VERSION 5.7 ;
  NOWIREEXTENSIONATPIN ON ;
  DIVIDERCHAR "/" ;
  BUSBITCHARS "[]" ;
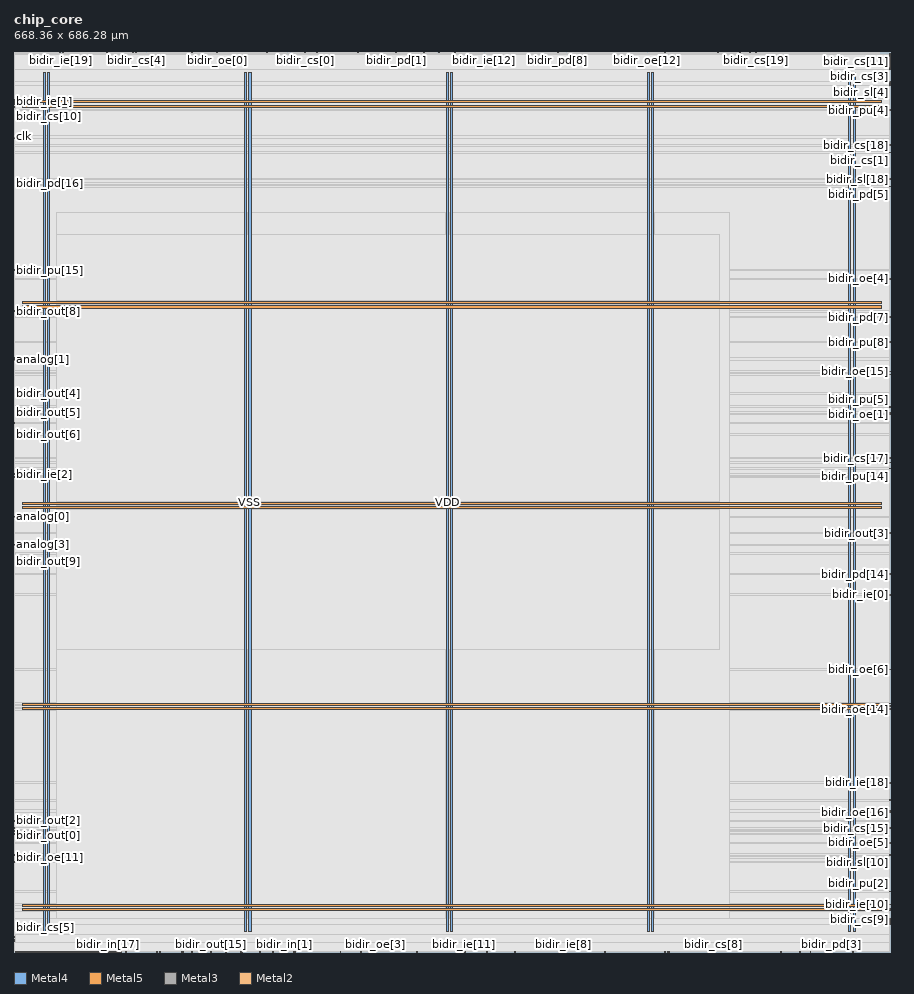
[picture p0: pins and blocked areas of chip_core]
MACRO chip_core
  CLASS BLOCK ;
  FOREIGN chip_core ;
  ORIGIN 0.000 0.000 ;
  SIZE 668.360 BY 686.280 ;
  PIN VDD
    DIRECTION INOUT ;
    USE POWER ;
    PORT
      LAYER Metal4 ;
        RECT 22.240 15.380 23.840 670.620 ;
    END
    PORT
      LAYER Metal4 ;
        RECT 175.840 15.380 177.440 670.620 ;
    END
    PORT
      LAYER Metal4 ;
        RECT 329.440 15.380 331.040 670.620 ;
    END
    PORT
      LAYER Metal4 ;
        RECT 483.040 15.380 484.640 670.620 ;
    END
    PORT
      LAYER Metal4 ;
        RECT 636.640 15.380 638.240 670.620 ;
    END
    PORT
      LAYER Metal5 ;
        RECT 6.720 31.530 661.360 33.130 ;
    END
    PORT
      LAYER Metal5 ;
        RECT 6.720 184.710 661.360 186.310 ;
    END
    PORT
      LAYER Metal5 ;
        RECT 6.720 337.890 661.360 339.490 ;
    END
    PORT
      LAYER Metal5 ;
        RECT 6.720 491.070 661.360 492.670 ;
    END
    PORT
      LAYER Metal5 ;
        RECT 6.720 644.250 661.360 645.850 ;
    END
  END VDD
  PIN VSS
    DIRECTION INOUT ;
    USE GROUND ;
    PORT
      LAYER Metal4 ;
        RECT 25.540 15.380 27.140 670.620 ;
    END
    PORT
      LAYER Metal4 ;
        RECT 179.140 15.380 180.740 670.620 ;
    END
    PORT
      LAYER Metal4 ;
        RECT 332.740 15.380 334.340 670.620 ;
    END
    PORT
      LAYER Metal4 ;
        RECT 486.340 15.380 487.940 670.620 ;
    END
    PORT
      LAYER Metal4 ;
        RECT 639.940 15.380 641.540 670.620 ;
    END
    PORT
      LAYER Metal5 ;
        RECT 6.720 34.830 661.360 36.430 ;
    END
    PORT
      LAYER Metal5 ;
        RECT 6.720 188.010 661.360 189.610 ;
    END
    PORT
      LAYER Metal5 ;
        RECT 6.720 341.190 661.360 342.790 ;
    END
    PORT
      LAYER Metal5 ;
        RECT 6.720 494.370 661.360 495.970 ;
    END
    PORT
      LAYER Metal5 ;
        RECT 6.720 647.550 661.360 649.150 ;
    END
  END VSS
  PIN analog[0]
    DIRECTION INOUT ;
    USE SIGNAL ;
    ANTENNAGATEAREA 1.017500 ;
    PORT
      LAYER Metal3 ;
        RECT 0.000 331.520 0.560 332.080 ;
    END
  END analog[0]
  PIN analog[10]
    DIRECTION INOUT ;
    USE SIGNAL ;
    PORT
      LAYER Metal2 ;
        RECT 1.120 0.000 1.680 0.560 ;
    END
  END analog[10]
  PIN analog[11]
    DIRECTION INOUT ;
    USE SIGNAL ;
    PORT
      LAYER Metal2 ;
        RECT 2.240 0.000 2.800 0.560 ;
    END
  END analog[11]
  PIN analog[12]
    DIRECTION INOUT ;
    USE SIGNAL ;
    PORT
      LAYER Metal2 ;
        RECT 3.360 0.000 3.920 0.560 ;
    END
  END analog[12]
  PIN analog[13]
    DIRECTION INOUT ;
    USE SIGNAL ;
    PORT
      LAYER Metal2 ;
        RECT 4.480 0.000 5.040 0.560 ;
    END
  END analog[13]
  PIN analog[14]
    DIRECTION INOUT ;
    USE SIGNAL ;
    PORT
      LAYER Metal2 ;
        RECT 5.600 0.000 6.160 0.560 ;
    END
  END analog[14]
  PIN analog[15]
    DIRECTION INOUT ;
    USE SIGNAL ;
    PORT
      LAYER Metal2 ;
        RECT 6.720 0.000 7.280 0.560 ;
    END
  END analog[15]
  PIN analog[16]
    DIRECTION INOUT ;
    USE SIGNAL ;
    PORT
      LAYER Metal2 ;
        RECT 7.840 0.000 8.400 0.560 ;
    END
  END analog[16]
  PIN analog[17]
    DIRECTION INOUT ;
    USE SIGNAL ;
    PORT
      LAYER Metal2 ;
        RECT 8.960 0.000 9.520 0.560 ;
    END
  END analog[17]
  PIN analog[18]
    DIRECTION INOUT ;
    USE SIGNAL ;
    PORT
      LAYER Metal2 ;
        RECT 10.080 0.000 10.640 0.560 ;
    END
  END analog[18]
  PIN analog[19]
    DIRECTION INOUT ;
    USE SIGNAL ;
    PORT
      LAYER Metal2 ;
        RECT 11.200 0.000 11.760 0.560 ;
    END
  END analog[19]
  PIN analog[1]
    DIRECTION INOUT ;
    USE SIGNAL ;
    ANTENNAGATEAREA 1.536500 ;
    ANTENNADIFFAREA 0.893200 ;
    PORT
      LAYER Metal3 ;
        RECT 0.000 451.360 0.560 451.920 ;
    END
  END analog[1]
  PIN analog[20]
    DIRECTION INOUT ;
    USE SIGNAL ;
    PORT
      LAYER Metal2 ;
        RECT 12.320 0.000 12.880 0.560 ;
    END
  END analog[20]
  PIN analog[21]
    DIRECTION INOUT ;
    USE SIGNAL ;
    PORT
      LAYER Metal2 ;
        RECT 13.440 0.000 14.000 0.560 ;
    END
  END analog[21]
  PIN analog[22]
    DIRECTION INOUT ;
    USE SIGNAL ;
    PORT
      LAYER Metal2 ;
        RECT 14.560 0.000 15.120 0.560 ;
    END
  END analog[22]
  PIN analog[23]
    DIRECTION INOUT ;
    USE SIGNAL ;
    PORT
      LAYER Metal2 ;
        RECT 15.680 0.000 16.240 0.560 ;
    END
  END analog[23]
  PIN analog[24]
    DIRECTION INOUT ;
    USE SIGNAL ;
    PORT
      LAYER Metal2 ;
        RECT 16.800 0.000 17.360 0.560 ;
    END
  END analog[24]
  PIN analog[25]
    DIRECTION INOUT ;
    USE SIGNAL ;
    PORT
      LAYER Metal2 ;
        RECT 17.920 0.000 18.480 0.560 ;
    END
  END analog[25]
  PIN analog[26]
    DIRECTION INOUT ;
    USE SIGNAL ;
    PORT
      LAYER Metal2 ;
        RECT 19.040 0.000 19.600 0.560 ;
    END
  END analog[26]
  PIN analog[27]
    DIRECTION INOUT ;
    USE SIGNAL ;
    PORT
      LAYER Metal2 ;
        RECT 20.160 0.000 20.720 0.560 ;
    END
  END analog[27]
  PIN analog[28]
    DIRECTION INOUT ;
    USE SIGNAL ;
    PORT
      LAYER Metal2 ;
        RECT 21.280 0.000 21.840 0.560 ;
    END
  END analog[28]
  PIN analog[29]
    DIRECTION INOUT ;
    USE SIGNAL ;
    PORT
      LAYER Metal2 ;
        RECT 22.400 0.000 22.960 0.560 ;
    END
  END analog[29]
  PIN analog[2]
    DIRECTION INOUT ;
    USE SIGNAL ;
    ANTENNAGATEAREA 0.894500 ;
    ANTENNADIFFAREA 0.893200 ;
    PORT
      LAYER Metal3 ;
        RECT 0.000 452.480 0.560 453.040 ;
    END
  END analog[2]
  PIN analog[30]
    DIRECTION INOUT ;
    USE SIGNAL ;
    PORT
      LAYER Metal2 ;
        RECT 23.520 0.000 24.080 0.560 ;
    END
  END analog[30]
  PIN analog[31]
    DIRECTION INOUT ;
    USE SIGNAL ;
    PORT
      LAYER Metal2 ;
        RECT 24.640 0.000 25.200 0.560 ;
    END
  END analog[31]
  PIN analog[32]
    DIRECTION INOUT ;
    USE SIGNAL ;
    PORT
      LAYER Metal2 ;
        RECT 25.760 0.000 26.320 0.560 ;
    END
  END analog[32]
  PIN analog[33]
    DIRECTION INOUT ;
    USE SIGNAL ;
    PORT
      LAYER Metal2 ;
        RECT 26.880 0.000 27.440 0.560 ;
    END
  END analog[33]
  PIN analog[34]
    DIRECTION INOUT ;
    USE SIGNAL ;
    PORT
      LAYER Metal2 ;
        RECT 28.000 0.000 28.560 0.560 ;
    END
  END analog[34]
  PIN analog[35]
    DIRECTION INOUT ;
    USE SIGNAL ;
    PORT
      LAYER Metal2 ;
        RECT 29.120 0.000 29.680 0.560 ;
    END
  END analog[35]
  PIN analog[36]
    DIRECTION INOUT ;
    USE SIGNAL ;
    PORT
      LAYER Metal2 ;
        RECT 30.240 0.000 30.800 0.560 ;
    END
  END analog[36]
  PIN analog[37]
    DIRECTION INOUT ;
    USE SIGNAL ;
    PORT
      LAYER Metal2 ;
        RECT 31.360 0.000 31.920 0.560 ;
    END
  END analog[37]
  PIN analog[38]
    DIRECTION INOUT ;
    USE SIGNAL ;
    PORT
      LAYER Metal2 ;
        RECT 32.480 0.000 33.040 0.560 ;
    END
  END analog[38]
  PIN analog[39]
    DIRECTION INOUT ;
    USE SIGNAL ;
    PORT
      LAYER Metal2 ;
        RECT 33.600 0.000 34.160 0.560 ;
    END
  END analog[39]
  PIN analog[3]
    DIRECTION INOUT ;
    USE SIGNAL ;
    ANTENNAGATEAREA 0.894500 ;
    ANTENNADIFFAREA 0.893200 ;
    PORT
      LAYER Metal3 ;
        RECT 0.000 310.240 0.560 310.800 ;
    END
  END analog[3]
  PIN analog[40]
    DIRECTION INOUT ;
    USE SIGNAL ;
    PORT
      LAYER Metal2 ;
        RECT 34.720 0.000 35.280 0.560 ;
    END
  END analog[40]
  PIN analog[41]
    DIRECTION INOUT ;
    USE SIGNAL ;
    PORT
      LAYER Metal2 ;
        RECT 35.840 0.000 36.400 0.560 ;
    END
  END analog[41]
  PIN analog[42]
    DIRECTION INOUT ;
    USE SIGNAL ;
    PORT
      LAYER Metal2 ;
        RECT 36.960 0.000 37.520 0.560 ;
    END
  END analog[42]
  PIN analog[43]
    DIRECTION INOUT ;
    USE SIGNAL ;
    PORT
      LAYER Metal2 ;
        RECT 38.080 0.000 38.640 0.560 ;
    END
  END analog[43]
  PIN analog[44]
    DIRECTION INOUT ;
    USE SIGNAL ;
    PORT
      LAYER Metal2 ;
        RECT 39.200 0.000 39.760 0.560 ;
    END
  END analog[44]
  PIN analog[45]
    DIRECTION INOUT ;
    USE SIGNAL ;
    PORT
      LAYER Metal2 ;
        RECT 40.320 0.000 40.880 0.560 ;
    END
  END analog[45]
  PIN analog[46]
    DIRECTION INOUT ;
    USE SIGNAL ;
    PORT
      LAYER Metal2 ;
        RECT 41.440 0.000 42.000 0.560 ;
    END
  END analog[46]
  PIN analog[47]
    DIRECTION INOUT ;
    USE SIGNAL ;
    PORT
      LAYER Metal2 ;
        RECT 42.560 0.000 43.120 0.560 ;
    END
  END analog[47]
  PIN analog[48]
    DIRECTION INOUT ;
    USE SIGNAL ;
    PORT
      LAYER Metal2 ;
        RECT 43.680 0.000 44.240 0.560 ;
    END
  END analog[48]
  PIN analog[49]
    DIRECTION INOUT ;
    USE SIGNAL ;
    PORT
      LAYER Metal2 ;
        RECT 44.800 0.000 45.360 0.560 ;
    END
  END analog[49]
  PIN analog[4]
    DIRECTION INOUT ;
    USE SIGNAL ;
    PORT
      LAYER Metal2 ;
        RECT 45.920 0.000 46.480 0.560 ;
    END
  END analog[4]
  PIN analog[50]
    DIRECTION INOUT ;
    USE SIGNAL ;
    PORT
      LAYER Metal2 ;
        RECT 47.040 0.000 47.600 0.560 ;
    END
  END analog[50]
  PIN analog[51]
    DIRECTION INOUT ;
    USE SIGNAL ;
    PORT
      LAYER Metal2 ;
        RECT 48.160 0.000 48.720 0.560 ;
    END
  END analog[51]
  PIN analog[52]
    DIRECTION INOUT ;
    USE SIGNAL ;
    PORT
      LAYER Metal2 ;
        RECT 49.280 0.000 49.840 0.560 ;
    END
  END analog[52]
  PIN analog[53]
    DIRECTION INOUT ;
    USE SIGNAL ;
    PORT
      LAYER Metal2 ;
        RECT 50.400 0.000 50.960 0.560 ;
    END
  END analog[53]
  PIN analog[54]
    DIRECTION INOUT ;
    USE SIGNAL ;
    PORT
      LAYER Metal2 ;
        RECT 51.520 0.000 52.080 0.560 ;
    END
  END analog[54]
  PIN analog[55]
    DIRECTION INOUT ;
    USE SIGNAL ;
    PORT
      LAYER Metal2 ;
        RECT 52.640 0.000 53.200 0.560 ;
    END
  END analog[55]
  PIN analog[56]
    DIRECTION INOUT ;
    USE SIGNAL ;
    PORT
      LAYER Metal2 ;
        RECT 53.760 0.000 54.320 0.560 ;
    END
  END analog[56]
  PIN analog[57]
    DIRECTION INOUT ;
    USE SIGNAL ;
    PORT
      LAYER Metal2 ;
        RECT 54.880 0.000 55.440 0.560 ;
    END
  END analog[57]
  PIN analog[58]
    DIRECTION INOUT ;
    USE SIGNAL ;
    PORT
      LAYER Metal2 ;
        RECT 56.000 0.000 56.560 0.560 ;
    END
  END analog[58]
  PIN analog[59]
    DIRECTION INOUT ;
    USE SIGNAL ;
    PORT
      LAYER Metal2 ;
        RECT 57.120 0.000 57.680 0.560 ;
    END
  END analog[59]
  PIN analog[5]
    DIRECTION INOUT ;
    USE SIGNAL ;
    PORT
      LAYER Metal2 ;
        RECT 58.240 0.000 58.800 0.560 ;
    END
  END analog[5]
  PIN analog[6]
    DIRECTION INOUT ;
    USE SIGNAL ;
    PORT
      LAYER Metal2 ;
        RECT 59.360 0.000 59.920 0.560 ;
    END
  END analog[6]
  PIN analog[7]
    DIRECTION INOUT ;
    USE SIGNAL ;
    PORT
      LAYER Metal2 ;
        RECT 60.480 0.000 61.040 0.560 ;
    END
  END analog[7]
  PIN analog[8]
    DIRECTION INOUT ;
    USE SIGNAL ;
    PORT
      LAYER Metal2 ;
        RECT 61.600 0.000 62.160 0.560 ;
    END
  END analog[8]
  PIN analog[9]
    DIRECTION INOUT ;
    USE SIGNAL ;
    PORT
      LAYER Metal2 ;
        RECT 62.720 0.000 63.280 0.560 ;
    END
  END analog[9]
  PIN bidir_cs[0]
    DIRECTION OUTPUT ;
    USE SIGNAL ;
    ANTENNADIFFAREA 0.536800 ;
    PORT
      LAYER Metal2 ;
        RECT 221.760 685.720 222.320 686.280 ;
    END
  END bidir_cs[0]
  PIN bidir_cs[10]
    DIRECTION OUTPUT ;
    USE SIGNAL ;
    ANTENNADIFFAREA 0.360800 ;
    PORT
      LAYER Metal3 ;
        RECT 0.000 642.880 0.560 643.440 ;
    END
  END bidir_cs[10]
  PIN bidir_cs[11]
    DIRECTION OUTPUT ;
    USE SIGNAL ;
    ANTENNADIFFAREA 0.360800 ;
    PORT
      LAYER Metal3 ;
        RECT 667.800 678.720 668.360 679.280 ;
    END
  END bidir_cs[11]
  PIN bidir_cs[12]
    DIRECTION OUTPUT ;
    USE SIGNAL ;
    ANTENNADIFFAREA 0.360800 ;
    PORT
      LAYER Metal3 ;
        RECT 0.000 7.840 0.560 8.400 ;
    END
  END bidir_cs[12]
  PIN bidir_cs[13]
    DIRECTION OUTPUT ;
    USE SIGNAL ;
    ANTENNADIFFAREA 0.360800 ;
    PORT
      LAYER Metal3 ;
        RECT 0.000 10.080 0.560 10.640 ;
    END
  END bidir_cs[13]
  PIN bidir_cs[14]
    DIRECTION OUTPUT ;
    USE SIGNAL ;
    ANTENNADIFFAREA 0.360800 ;
    PORT
      LAYER Metal2 ;
        RECT 85.120 0.000 85.680 0.560 ;
    END
  END bidir_cs[14]
  PIN bidir_cs[15]
    DIRECTION OUTPUT ;
    USE SIGNAL ;
    ANTENNADIFFAREA 0.360800 ;
    PORT
      LAYER Metal3 ;
        RECT 667.800 94.080 668.360 94.640 ;
    END
  END bidir_cs[15]
  PIN bidir_cs[16]
    DIRECTION OUTPUT ;
    USE SIGNAL ;
    ANTENNADIFFAREA 0.360800 ;
    PORT
      LAYER Metal2 ;
        RECT 34.720 685.720 35.280 686.280 ;
    END
  END bidir_cs[16]
  PIN bidir_cs[17]
    DIRECTION OUTPUT ;
    USE SIGNAL ;
    ANTENNADIFFAREA 0.360800 ;
    PORT
      LAYER Metal3 ;
        RECT 667.800 376.320 668.360 376.880 ;
    END
  END bidir_cs[17]
  PIN bidir_cs[18]
    DIRECTION OUTPUT ;
    USE SIGNAL ;
    ANTENNADIFFAREA 0.360800 ;
    PORT
      LAYER Metal3 ;
        RECT 667.800 614.880 668.360 615.440 ;
    END
  END bidir_cs[18]
  PIN bidir_cs[19]
    DIRECTION OUTPUT ;
    USE SIGNAL ;
    ANTENNADIFFAREA 0.360800 ;
    PORT
      LAYER Metal2 ;
        RECT 565.600 685.720 566.160 686.280 ;
    END
  END bidir_cs[19]
  PIN bidir_cs[1]
    DIRECTION OUTPUT ;
    USE SIGNAL ;
    ANTENNADIFFAREA 0.536800 ;
    PORT
      LAYER Metal3 ;
        RECT 667.800 609.280 668.360 609.840 ;
    END
  END bidir_cs[1]
  PIN bidir_cs[2]
    DIRECTION OUTPUT ;
    USE SIGNAL ;
    ANTENNADIFFAREA 0.536800 ;
    PORT
      LAYER Metal3 ;
        RECT 667.800 31.360 668.360 31.920 ;
    END
  END bidir_cs[2]
  PIN bidir_cs[3]
    DIRECTION OUTPUT ;
    USE SIGNAL ;
    ANTENNADIFFAREA 0.360800 ;
    PORT
      LAYER Metal3 ;
        RECT 667.800 673.120 668.360 673.680 ;
    END
  END bidir_cs[3]
  PIN bidir_cs[4]
    DIRECTION OUTPUT ;
    USE SIGNAL ;
    ANTENNADIFFAREA 0.360800 ;
    PORT
      LAYER Metal2 ;
        RECT 92.960 685.720 93.520 686.280 ;
    END
  END bidir_cs[4]
  PIN bidir_cs[5]
    DIRECTION OUTPUT ;
    USE SIGNAL ;
    ANTENNADIFFAREA 0.360800 ;
    PORT
      LAYER Metal3 ;
        RECT 0.000 12.320 0.560 12.880 ;
    END
  END bidir_cs[5]
  PIN bidir_cs[6]
    DIRECTION OUTPUT ;
    USE SIGNAL ;
    ANTENNADIFFAREA 0.360800 ;
    PORT
      LAYER Metal2 ;
        RECT 499.520 0.000 500.080 0.560 ;
    END
  END bidir_cs[6]
  PIN bidir_cs[7]
    DIRECTION OUTPUT ;
    USE SIGNAL ;
    ANTENNADIFFAREA 0.360800 ;
    PORT
      LAYER Metal3 ;
        RECT 667.800 675.360 668.360 675.920 ;
    END
  END bidir_cs[7]
  PIN bidir_cs[8]
    DIRECTION OUTPUT ;
    USE SIGNAL ;
    ANTENNADIFFAREA 0.360800 ;
    PORT
      LAYER Metal2 ;
        RECT 533.120 0.000 533.680 0.560 ;
    END
  END bidir_cs[8]
  PIN bidir_cs[9]
    DIRECTION OUTPUT ;
    USE SIGNAL ;
    ANTENNADIFFAREA 0.360800 ;
    PORT
      LAYER Metal3 ;
        RECT 667.800 24.640 668.360 25.200 ;
    END
  END bidir_cs[9]
  PIN bidir_ie[0]
    DIRECTION OUTPUT ;
    USE SIGNAL ;
    ANTENNADIFFAREA 0.536800 ;
    PORT
      LAYER Metal3 ;
        RECT 667.800 272.160 668.360 272.720 ;
    END
  END bidir_ie[0]
  PIN bidir_ie[10]
    DIRECTION OUTPUT ;
    USE SIGNAL ;
    ANTENNADIFFAREA 0.360800 ;
    PORT
      LAYER Metal3 ;
        RECT 667.800 35.840 668.360 36.400 ;
    END
  END bidir_ie[10]
  PIN bidir_ie[11]
    DIRECTION OUTPUT ;
    USE SIGNAL ;
    ANTENNADIFFAREA 0.360800 ;
    PORT
      LAYER Metal2 ;
        RECT 342.720 0.000 343.280 0.560 ;
    END
  END bidir_ie[11]
  PIN bidir_ie[12]
    DIRECTION OUTPUT ;
    USE SIGNAL ;
    ANTENNADIFFAREA 0.360800 ;
    PORT
      LAYER Metal2 ;
        RECT 358.400 685.720 358.960 686.280 ;
    END
  END bidir_ie[12]
  PIN bidir_ie[13]
    DIRECTION OUTPUT ;
    USE SIGNAL ;
    ANTENNADIFFAREA 0.360800 ;
    PORT
      LAYER Metal2 ;
        RECT 208.320 685.720 208.880 686.280 ;
    END
  END bidir_ie[13]
  PIN bidir_ie[14]
    DIRECTION OUTPUT ;
    USE SIGNAL ;
    ANTENNADIFFAREA 0.360800 ;
    PORT
      LAYER Metal3 ;
        RECT 0.000 68.320 0.560 68.880 ;
    END
  END bidir_ie[14]
  PIN bidir_ie[15]
    DIRECTION OUTPUT ;
    USE SIGNAL ;
    ANTENNADIFFAREA 0.360800 ;
    PORT
      LAYER Metal3 ;
        RECT 667.800 676.480 668.360 677.040 ;
    END
  END bidir_ie[15]
  PIN bidir_ie[16]
    DIRECTION OUTPUT ;
    USE SIGNAL ;
    ANTENNADIFFAREA 0.360800 ;
    PORT
      LAYER Metal3 ;
        RECT 667.800 682.080 668.360 682.640 ;
    END
  END bidir_ie[16]
  PIN bidir_ie[17]
    DIRECTION OUTPUT ;
    USE SIGNAL ;
    ANTENNADIFFAREA 0.360800 ;
    PORT
      LAYER Metal2 ;
        RECT 204.960 0.000 205.520 0.560 ;
    END
  END bidir_ie[17]
  PIN bidir_ie[18]
    DIRECTION OUTPUT ;
    USE SIGNAL ;
    ANTENNADIFFAREA 0.360800 ;
    PORT
      LAYER Metal3 ;
        RECT 667.800 128.800 668.360 129.360 ;
    END
  END bidir_ie[18]
  PIN bidir_ie[19]
    DIRECTION OUTPUT ;
    USE SIGNAL ;
    ANTENNADIFFAREA 0.360800 ;
    PORT
      LAYER Metal2 ;
        RECT 35.840 685.720 36.400 686.280 ;
    END
  END bidir_ie[19]
  PIN bidir_ie[1]
    DIRECTION OUTPUT ;
    USE SIGNAL ;
    ANTENNADIFFAREA 0.536800 ;
    PORT
      LAYER Metal3 ;
        RECT 0.000 648.480 0.560 649.040 ;
    END
  END bidir_ie[1]
  PIN bidir_ie[2]
    DIRECTION OUTPUT ;
    USE SIGNAL ;
    ANTENNADIFFAREA 0.536800 ;
    PORT
      LAYER Metal3 ;
        RECT 0.000 364.000 0.560 364.560 ;
    END
  END bidir_ie[2]
  PIN bidir_ie[3]
    DIRECTION OUTPUT ;
    USE SIGNAL ;
    ANTENNADIFFAREA 0.360800 ;
    PORT
      LAYER Metal3 ;
        RECT 0.000 647.360 0.560 647.920 ;
    END
  END bidir_ie[3]
  PIN bidir_ie[4]
    DIRECTION OUTPUT ;
    USE SIGNAL ;
    ANTENNADIFFAREA 0.360800 ;
    PORT
      LAYER Metal3 ;
        RECT 0.000 646.240 0.560 646.800 ;
    END
  END bidir_ie[4]
  PIN bidir_ie[5]
    DIRECTION OUTPUT ;
    USE SIGNAL ;
    ANTENNADIFFAREA 0.360800 ;
    PORT
      LAYER Metal3 ;
        RECT 667.800 680.960 668.360 681.520 ;
    END
  END bidir_ie[5]
  PIN bidir_ie[6]
    DIRECTION OUTPUT ;
    USE SIGNAL ;
    ANTENNADIFFAREA 0.360800 ;
    PORT
      LAYER Metal2 ;
        RECT 496.160 0.000 496.720 0.560 ;
    END
  END bidir_ie[6]
  PIN bidir_ie[7]
    DIRECTION OUTPUT ;
    USE SIGNAL ;
    ANTENNADIFFAREA 0.360800 ;
    PORT
      LAYER Metal2 ;
        RECT 212.800 0.000 213.360 0.560 ;
    END
  END bidir_ie[7]
  PIN bidir_ie[8]
    DIRECTION OUTPUT ;
    USE SIGNAL ;
    ANTENNADIFFAREA 0.360800 ;
    PORT
      LAYER Metal2 ;
        RECT 418.880 0.000 419.440 0.560 ;
    END
  END bidir_ie[8]
  PIN bidir_ie[9]
    DIRECTION OUTPUT ;
    USE SIGNAL ;
    ANTENNADIFFAREA 0.360800 ;
    PORT
      LAYER Metal3 ;
        RECT 667.800 23.520 668.360 24.080 ;
    END
  END bidir_ie[9]
  PIN bidir_in[0]
    DIRECTION INPUT ;
    USE SIGNAL ;
    ANTENNAGATEAREA 0.396000 ;
    PORT
      LAYER Metal2 ;
        RECT 213.920 0.000 214.480 0.560 ;
    END
  END bidir_in[0]
  PIN bidir_in[10]
    DIRECTION INPUT ;
    USE SIGNAL ;
    PORT
      LAYER Metal2 ;
        RECT 63.840 0.000 64.400 0.560 ;
    END
  END bidir_in[10]
  PIN bidir_in[11]
    DIRECTION INPUT ;
    USE SIGNAL ;
    PORT
      LAYER Metal2 ;
        RECT 64.960 0.000 65.520 0.560 ;
    END
  END bidir_in[11]
  PIN bidir_in[12]
    DIRECTION INPUT ;
    USE SIGNAL ;
    PORT
      LAYER Metal2 ;
        RECT 66.080 0.000 66.640 0.560 ;
    END
  END bidir_in[12]
  PIN bidir_in[13]
    DIRECTION INPUT ;
    USE SIGNAL ;
    PORT
      LAYER Metal2 ;
        RECT 67.200 0.000 67.760 0.560 ;
    END
  END bidir_in[13]
  PIN bidir_in[14]
    DIRECTION INPUT ;
    USE SIGNAL ;
    PORT
      LAYER Metal2 ;
        RECT 68.320 0.000 68.880 0.560 ;
    END
  END bidir_in[14]
  PIN bidir_in[15]
    DIRECTION INPUT ;
    USE SIGNAL ;
    PORT
      LAYER Metal2 ;
        RECT 69.440 0.000 70.000 0.560 ;
    END
  END bidir_in[15]
  PIN bidir_in[16]
    DIRECTION INPUT ;
    USE SIGNAL ;
    PORT
      LAYER Metal2 ;
        RECT 70.560 0.000 71.120 0.560 ;
    END
  END bidir_in[16]
  PIN bidir_in[17]
    DIRECTION INPUT ;
    USE SIGNAL ;
    PORT
      LAYER Metal2 ;
        RECT 71.680 0.000 72.240 0.560 ;
    END
  END bidir_in[17]
  PIN bidir_in[18]
    DIRECTION INPUT ;
    USE SIGNAL ;
    PORT
      LAYER Metal2 ;
        RECT 72.800 0.000 73.360 0.560 ;
    END
  END bidir_in[18]
  PIN bidir_in[19]
    DIRECTION INPUT ;
    USE SIGNAL ;
    PORT
      LAYER Metal2 ;
        RECT 73.920 0.000 74.480 0.560 ;
    END
  END bidir_in[19]
  PIN bidir_in[1]
    DIRECTION INPUT ;
    USE SIGNAL ;
    ANTENNAGATEAREA 0.396000 ;
    PORT
      LAYER Metal2 ;
        RECT 206.080 0.000 206.640 0.560 ;
    END
  END bidir_in[1]
  PIN bidir_in[2]
    DIRECTION INPUT ;
    USE SIGNAL ;
    ANTENNAGATEAREA 0.396000 ;
    PORT
      LAYER Metal2 ;
        RECT 172.480 0.000 173.040 0.560 ;
    END
  END bidir_in[2]
  PIN bidir_in[3]
    DIRECTION INPUT ;
    USE SIGNAL ;
    PORT
      LAYER Metal2 ;
        RECT 75.040 0.000 75.600 0.560 ;
    END
  END bidir_in[3]
  PIN bidir_in[4]
    DIRECTION INPUT ;
    USE SIGNAL ;
    PORT
      LAYER Metal2 ;
        RECT 76.160 0.000 76.720 0.560 ;
    END
  END bidir_in[4]
  PIN bidir_in[5]
    DIRECTION INPUT ;
    USE SIGNAL ;
    PORT
      LAYER Metal2 ;
        RECT 77.280 0.000 77.840 0.560 ;
    END
  END bidir_in[5]
  PIN bidir_in[6]
    DIRECTION INPUT ;
    USE SIGNAL ;
    PORT
      LAYER Metal2 ;
        RECT 78.400 0.000 78.960 0.560 ;
    END
  END bidir_in[6]
  PIN bidir_in[7]
    DIRECTION INPUT ;
    USE SIGNAL ;
    PORT
      LAYER Metal2 ;
        RECT 79.520 0.000 80.080 0.560 ;
    END
  END bidir_in[7]
  PIN bidir_in[8]
    DIRECTION INPUT ;
    USE SIGNAL ;
    PORT
      LAYER Metal2 ;
        RECT 80.640 0.000 81.200 0.560 ;
    END
  END bidir_in[8]
  PIN bidir_in[9]
    DIRECTION INPUT ;
    USE SIGNAL ;
    PORT
      LAYER Metal2 ;
        RECT 81.760 0.000 82.320 0.560 ;
    END
  END bidir_in[9]
  PIN bidir_oe[0]
    DIRECTION OUTPUT ;
    USE SIGNAL ;
    ANTENNADIFFAREA 0.360800 ;
    PORT
      LAYER Metal2 ;
        RECT 154.560 685.720 155.120 686.280 ;
    END
  END bidir_oe[0]
  PIN bidir_oe[10]
    DIRECTION OUTPUT ;
    USE SIGNAL ;
    ANTENNADIFFAREA 0.536800 ;
    PORT
      LAYER Metal3 ;
        RECT 667.800 107.520 668.360 108.080 ;
    END
  END bidir_oe[10]
  PIN bidir_oe[11]
    DIRECTION OUTPUT ;
    USE SIGNAL ;
    ANTENNADIFFAREA 0.536800 ;
    PORT
      LAYER Metal3 ;
        RECT 0.000 71.680 0.560 72.240 ;
    END
  END bidir_oe[11]
  PIN bidir_oe[12]
    DIRECTION OUTPUT ;
    USE SIGNAL ;
    ANTENNADIFFAREA 0.536800 ;
    PORT
      LAYER Metal2 ;
        RECT 482.720 685.720 483.280 686.280 ;
    END
  END bidir_oe[12]
  PIN bidir_oe[13]
    DIRECTION OUTPUT ;
    USE SIGNAL ;
    ANTENNADIFFAREA 0.536800 ;
    PORT
      LAYER Metal3 ;
        RECT 667.800 683.200 668.360 683.760 ;
    END
  END bidir_oe[13]
  PIN bidir_oe[14]
    DIRECTION OUTPUT ;
    USE SIGNAL ;
    ANTENNADIFFAREA 0.536800 ;
    PORT
      LAYER Metal3 ;
        RECT 667.800 184.800 668.360 185.360 ;
    END
  END bidir_oe[14]
  PIN bidir_oe[15]
    DIRECTION OUTPUT ;
    USE SIGNAL ;
    ANTENNADIFFAREA 0.536800 ;
    PORT
      LAYER Metal3 ;
        RECT 667.800 442.400 668.360 442.960 ;
    END
  END bidir_oe[15]
  PIN bidir_oe[16]
    DIRECTION OUTPUT ;
    USE SIGNAL ;
    ANTENNADIFFAREA 0.536800 ;
    PORT
      LAYER Metal3 ;
        RECT 667.800 106.400 668.360 106.960 ;
    END
  END bidir_oe[16]
  PIN bidir_oe[17]
    DIRECTION OUTPUT ;
    USE SIGNAL ;
    ANTENNADIFFAREA 0.536800 ;
    PORT
      LAYER Metal2 ;
        RECT 36.960 685.720 37.520 686.280 ;
    END
  END bidir_oe[17]
  PIN bidir_oe[18]
    DIRECTION OUTPUT ;
    USE SIGNAL ;
    ANTENNADIFFAREA 0.536800 ;
    PORT
      LAYER Metal3 ;
        RECT 0.000 73.920 0.560 74.480 ;
    END
  END bidir_oe[18]
  PIN bidir_oe[19]
    DIRECTION OUTPUT ;
    USE SIGNAL ;
    ANTENNADIFFAREA 0.536800 ;
    PORT
      LAYER Metal2 ;
        RECT 360.640 0.000 361.200 0.560 ;
    END
  END bidir_oe[19]
  PIN bidir_oe[1]
    DIRECTION OUTPUT ;
    USE SIGNAL ;
    ANTENNADIFFAREA 0.360800 ;
    PORT
      LAYER Metal3 ;
        RECT 667.800 409.920 668.360 410.480 ;
    END
  END bidir_oe[1]
  PIN bidir_oe[2]
    DIRECTION OUTPUT ;
    USE SIGNAL ;
    ANTENNADIFFAREA 0.360800 ;
    PORT
      LAYER Metal2 ;
        RECT 192.640 685.720 193.200 686.280 ;
    END
  END bidir_oe[2]
  PIN bidir_oe[3]
    DIRECTION OUTPUT ;
    USE SIGNAL ;
    ANTENNADIFFAREA 0.897600 ;
    PORT
      LAYER Metal2 ;
        RECT 275.520 0.000 276.080 0.560 ;
    END
  END bidir_oe[3]
  PIN bidir_oe[4]
    DIRECTION OUTPUT ;
    USE SIGNAL ;
    ANTENNADIFFAREA 0.536800 ;
    PORT
      LAYER Metal3 ;
        RECT 667.800 512.960 668.360 513.520 ;
    END
  END bidir_oe[4]
  PIN bidir_oe[5]
    DIRECTION OUTPUT ;
    USE SIGNAL ;
    ANTENNADIFFAREA 0.536800 ;
    PORT
      LAYER Metal3 ;
        RECT 667.800 82.880 668.360 83.440 ;
    END
  END bidir_oe[5]
  PIN bidir_oe[6]
    DIRECTION OUTPUT ;
    USE SIGNAL ;
    ANTENNADIFFAREA 0.536800 ;
    PORT
      LAYER Metal3 ;
        RECT 667.800 215.040 668.360 215.600 ;
    END
  END bidir_oe[6]
  PIN bidir_oe[7]
    DIRECTION OUTPUT ;
    USE SIGNAL ;
    ANTENNADIFFAREA 0.536800 ;
    PORT
      LAYER Metal3 ;
        RECT 667.800 187.040 668.360 187.600 ;
    END
  END bidir_oe[7]
  PIN bidir_oe[8]
    DIRECTION OUTPUT ;
    USE SIGNAL ;
    ANTENNADIFFAREA 0.536800 ;
    PORT
      LAYER Metal3 ;
        RECT 667.800 32.480 668.360 33.040 ;
    END
  END bidir_oe[8]
  PIN bidir_oe[9]
    DIRECTION OUTPUT ;
    USE SIGNAL ;
    ANTENNADIFFAREA 0.536800 ;
    PORT
      LAYER Metal2 ;
        RECT 230.720 685.720 231.280 686.280 ;
    END
  END bidir_oe[9]
  PIN bidir_out[0]
    DIRECTION OUTPUT ;
    USE SIGNAL ;
    ANTENNADIFFAREA 0.897600 ;
    PORT
      LAYER Metal3 ;
        RECT 0.000 94.080 0.560 94.640 ;
    END
  END bidir_out[0]
  PIN bidir_out[10]
    DIRECTION OUTPUT ;
    USE SIGNAL ;
    ANTENNADIFFAREA 0.897600 ;
    PORT
      LAYER Metal2 ;
        RECT 108.640 0.000 109.200 0.560 ;
    END
  END bidir_out[10]
  PIN bidir_out[11]
    DIRECTION OUTPUT ;
    USE SIGNAL ;
    ANTENNADIFFAREA 0.897600 ;
    PORT
      LAYER Metal2 ;
        RECT 110.880 0.000 111.440 0.560 ;
    END
  END bidir_out[11]
  PIN bidir_out[12]
    DIRECTION OUTPUT ;
    USE SIGNAL ;
    ANTENNADIFFAREA 0.897600 ;
    PORT
      LAYER Metal2 ;
        RECT 128.800 0.000 129.360 0.560 ;
    END
  END bidir_out[12]
  PIN bidir_out[13]
    DIRECTION OUTPUT ;
    USE SIGNAL ;
    ANTENNADIFFAREA 0.897600 ;
    PORT
      LAYER Metal2 ;
        RECT 127.680 0.000 128.240 0.560 ;
    END
  END bidir_out[13]
  PIN bidir_out[14]
    DIRECTION OUTPUT ;
    USE SIGNAL ;
    ANTENNADIFFAREA 0.897600 ;
    PORT
      LAYER Metal2 ;
        RECT 135.520 0.000 136.080 0.560 ;
    END
  END bidir_out[14]
  PIN bidir_out[15]
    DIRECTION OUTPUT ;
    USE SIGNAL ;
    ANTENNADIFFAREA 0.897600 ;
    PORT
      LAYER Metal2 ;
        RECT 150.080 0.000 150.640 0.560 ;
    END
  END bidir_out[15]
  PIN bidir_out[16]
    DIRECTION OUTPUT ;
    USE SIGNAL ;
    ANTENNADIFFAREA 0.897600 ;
    PORT
      LAYER Metal2 ;
        RECT 161.280 0.000 161.840 0.560 ;
    END
  END bidir_out[16]
  PIN bidir_out[17]
    DIRECTION OUTPUT ;
    USE SIGNAL ;
    ANTENNADIFFAREA 0.897600 ;
    PORT
      LAYER Metal2 ;
        RECT 173.600 0.000 174.160 0.560 ;
    END
  END bidir_out[17]
  PIN bidir_out[18]
    DIRECTION OUTPUT ;
    USE SIGNAL ;
    ANTENNADIFFAREA 0.897600 ;
    PORT
      LAYER Metal2 ;
        RECT 187.040 0.000 187.600 0.560 ;
    END
  END bidir_out[18]
  PIN bidir_out[19]
    DIRECTION OUTPUT ;
    USE SIGNAL ;
    ANTENNADIFFAREA 0.897600 ;
    PORT
      LAYER Metal2 ;
        RECT 197.120 0.000 197.680 0.560 ;
    END
  END bidir_out[19]
  PIN bidir_out[1]
    DIRECTION OUTPUT ;
    USE SIGNAL ;
    ANTENNADIFFAREA 0.897600 ;
    PORT
      LAYER Metal3 ;
        RECT 0.000 89.600 0.560 90.160 ;
    END
  END bidir_out[1]
  PIN bidir_out[2]
    DIRECTION OUTPUT ;
    USE SIGNAL ;
    ANTENNADIFFAREA 0.897600 ;
    PORT
      LAYER Metal3 ;
        RECT 0.000 99.680 0.560 100.240 ;
    END
  END bidir_out[2]
  PIN bidir_out[3]
    DIRECTION OUTPUT ;
    USE SIGNAL ;
    ANTENNADIFFAREA 0.897600 ;
    PORT
      LAYER Metal3 ;
        RECT 667.800 319.200 668.360 319.760 ;
    END
  END bidir_out[3]
  PIN bidir_out[4]
    DIRECTION OUTPUT ;
    USE SIGNAL ;
    ANTENNADIFFAREA 0.897600 ;
    PORT
      LAYER Metal3 ;
        RECT 0.000 425.600 0.560 426.160 ;
    END
  END bidir_out[4]
  PIN bidir_out[5]
    DIRECTION OUTPUT ;
    USE SIGNAL ;
    ANTENNADIFFAREA 0.897600 ;
    PORT
      LAYER Metal3 ;
        RECT 0.000 411.040 0.560 411.600 ;
    END
  END bidir_out[5]
  PIN bidir_out[6]
    DIRECTION OUTPUT ;
    USE SIGNAL ;
    ANTENNADIFFAREA 0.897600 ;
    PORT
      LAYER Metal3 ;
        RECT 0.000 394.240 0.560 394.800 ;
    END
  END bidir_out[6]
  PIN bidir_out[7]
    DIRECTION OUTPUT ;
    USE SIGNAL ;
    ANTENNADIFFAREA 0.897600 ;
    PORT
      LAYER Metal3 ;
        RECT 0.000 403.200 0.560 403.760 ;
    END
  END bidir_out[7]
  PIN bidir_out[8]
    DIRECTION OUTPUT ;
    USE SIGNAL ;
    ANTENNADIFFAREA 0.897600 ;
    PORT
      LAYER Metal3 ;
        RECT 0.000 488.320 0.560 488.880 ;
    END
  END bidir_out[8]
  PIN bidir_out[9]
    DIRECTION OUTPUT ;
    USE SIGNAL ;
    ANTENNADIFFAREA 0.897600 ;
    PORT
      LAYER Metal3 ;
        RECT 0.000 303.520 0.560 304.080 ;
    END
  END bidir_out[9]
  PIN bidir_pd[0]
    DIRECTION OUTPUT ;
    USE SIGNAL ;
    ANTENNADIFFAREA 0.360800 ;
    PORT
      LAYER Metal3 ;
        RECT 667.800 440.160 668.360 440.720 ;
    END
  END bidir_pd[0]
  PIN bidir_pd[10]
    DIRECTION OUTPUT ;
    USE SIGNAL ;
    ANTENNADIFFAREA 0.360800 ;
    PORT
      LAYER Metal3 ;
        RECT 0.000 645.120 0.560 645.680 ;
    END
  END bidir_pd[10]
  PIN bidir_pd[11]
    DIRECTION OUTPUT ;
    USE SIGNAL ;
    ANTENNADIFFAREA 0.360800 ;
    PORT
      LAYER Metal3 ;
        RECT 0.000 11.200 0.560 11.760 ;
    END
  END bidir_pd[11]
  PIN bidir_pd[12]
    DIRECTION OUTPUT ;
    USE SIGNAL ;
    ANTENNADIFFAREA 0.360800 ;
    PORT
      LAYER Metal2 ;
        RECT 450.240 0.000 450.800 0.560 ;
    END
  END bidir_pd[12]
  PIN bidir_pd[13]
    DIRECTION OUTPUT ;
    USE SIGNAL ;
    ANTENNADIFFAREA 0.360800 ;
    PORT
      LAYER Metal2 ;
        RECT 340.480 0.000 341.040 0.560 ;
    END
  END bidir_pd[13]
  PIN bidir_pd[14]
    DIRECTION OUTPUT ;
    USE SIGNAL ;
    ANTENNADIFFAREA 0.360800 ;
    PORT
      LAYER Metal3 ;
        RECT 667.800 287.840 668.360 288.400 ;
    END
  END bidir_pd[14]
  PIN bidir_pd[15]
    DIRECTION OUTPUT ;
    USE SIGNAL ;
    ANTENNADIFFAREA 0.360800 ;
    PORT
      LAYER Metal2 ;
        RECT 70.560 685.720 71.120 686.280 ;
    END
  END bidir_pd[15]
  PIN bidir_pd[16]
    DIRECTION OUTPUT ;
    USE SIGNAL ;
    ANTENNADIFFAREA 0.360800 ;
    PORT
      LAYER Metal3 ;
        RECT 0.000 585.760 0.560 586.320 ;
    END
  END bidir_pd[16]
  PIN bidir_pd[17]
    DIRECTION OUTPUT ;
    USE SIGNAL ;
    ANTENNADIFFAREA 0.360800 ;
    PORT
      LAYER Metal2 ;
        RECT 322.560 685.720 323.120 686.280 ;
    END
  END bidir_pd[17]
  PIN bidir_pd[18]
    DIRECTION OUTPUT ;
    USE SIGNAL ;
    ANTENNADIFFAREA 0.360800 ;
    PORT
      LAYER Metal3 ;
        RECT 667.800 674.240 668.360 674.800 ;
    END
  END bidir_pd[18]
  PIN bidir_pd[19]
    DIRECTION OUTPUT ;
    USE SIGNAL ;
    ANTENNADIFFAREA 0.360800 ;
    PORT
      LAYER Metal3 ;
        RECT 667.800 189.280 668.360 189.840 ;
    END
  END bidir_pd[19]
  PIN bidir_pd[1]
    DIRECTION OUTPUT ;
    USE SIGNAL ;
    ANTENNADIFFAREA 0.360800 ;
    PORT
      LAYER Metal2 ;
        RECT 291.200 685.720 291.760 686.280 ;
    END
  END bidir_pd[1]
  PIN bidir_pd[2]
    DIRECTION OUTPUT ;
    USE SIGNAL ;
    ANTENNADIFFAREA 0.360800 ;
    PORT
      LAYER Metal3 ;
        RECT 667.800 22.400 668.360 22.960 ;
    END
  END bidir_pd[2]
  PIN bidir_pd[3]
    DIRECTION OUTPUT ;
    USE SIGNAL ;
    ANTENNADIFFAREA 0.360800 ;
    PORT
      LAYER Metal2 ;
        RECT 622.720 0.000 623.280 0.560 ;
    END
  END bidir_pd[3]
  PIN bidir_pd[4]
    DIRECTION OUTPUT ;
    USE SIGNAL ;
    ANTENNADIFFAREA 0.360800 ;
    PORT
      LAYER Metal2 ;
        RECT 343.840 0.000 344.400 0.560 ;
    END
  END bidir_pd[4]
  PIN bidir_pd[5]
    DIRECTION OUTPUT ;
    USE SIGNAL ;
    ANTENNADIFFAREA 0.360800 ;
    PORT
      LAYER Metal3 ;
        RECT 667.800 583.520 668.360 584.080 ;
    END
  END bidir_pd[5]
  PIN bidir_pd[6]
    DIRECTION OUTPUT ;
    USE SIGNAL ;
    ANTENNADIFFAREA 0.360800 ;
    PORT
      LAYER Metal3 ;
        RECT 0.000 644.000 0.560 644.560 ;
    END
  END bidir_pd[6]
  PIN bidir_pd[7]
    DIRECTION OUTPUT ;
    USE SIGNAL ;
    ANTENNADIFFAREA 0.360800 ;
    PORT
      LAYER Metal3 ;
        RECT 667.800 483.840 668.360 484.400 ;
    END
  END bidir_pd[7]
  PIN bidir_pd[8]
    DIRECTION OUTPUT ;
    USE SIGNAL ;
    ANTENNADIFFAREA 0.360800 ;
    PORT
      LAYER Metal2 ;
        RECT 414.400 685.720 414.960 686.280 ;
    END
  END bidir_pd[8]
  PIN bidir_pd[9]
    DIRECTION OUTPUT ;
    USE SIGNAL ;
    ANTENNADIFFAREA 0.360800 ;
    PORT
      LAYER Metal3 ;
        RECT 667.800 679.840 668.360 680.400 ;
    END
  END bidir_pd[9]
  PIN bidir_pu[0]
    DIRECTION OUTPUT ;
    USE SIGNAL ;
    ANTENNADIFFAREA 0.536800 ;
    PORT
      LAYER Metal3 ;
        RECT 0.000 8.960 0.560 9.520 ;
    END
  END bidir_pu[0]
  PIN bidir_pu[10]
    DIRECTION OUTPUT ;
    USE SIGNAL ;
    ANTENNADIFFAREA 0.360800 ;
    PORT
      LAYER Metal2 ;
        RECT 599.200 0.000 599.760 0.560 ;
    END
  END bidir_pu[10]
  PIN bidir_pu[11]
    DIRECTION OUTPUT ;
    USE SIGNAL ;
    ANTENNADIFFAREA 0.360800 ;
    PORT
      LAYER Metal2 ;
        RECT 553.280 685.720 553.840 686.280 ;
    END
  END bidir_pu[11]
  PIN bidir_pu[12]
    DIRECTION OUTPUT ;
    USE SIGNAL ;
    ANTENNADIFFAREA 0.360800 ;
    PORT
      LAYER Metal3 ;
        RECT 667.800 677.600 668.360 678.160 ;
    END
  END bidir_pu[12]
  PIN bidir_pu[13]
    DIRECTION OUTPUT ;
    USE SIGNAL ;
    ANTENNADIFFAREA 0.360800 ;
    PORT
      LAYER Metal2 ;
        RECT 498.400 0.000 498.960 0.560 ;
    END
  END bidir_pu[13]
  PIN bidir_pu[14]
    DIRECTION OUTPUT ;
    USE SIGNAL ;
    ANTENNADIFFAREA 0.360800 ;
    PORT
      LAYER Metal3 ;
        RECT 667.800 368.480 668.360 369.040 ;
    END
  END bidir_pu[14]
  PIN bidir_pu[15]
    DIRECTION OUTPUT ;
    USE SIGNAL ;
    ANTENNADIFFAREA 0.360800 ;
    PORT
      LAYER Metal3 ;
        RECT 0.000 519.680 0.560 520.240 ;
    END
  END bidir_pu[15]
  PIN bidir_pu[16]
    DIRECTION OUTPUT ;
    USE SIGNAL ;
    ANTENNADIFFAREA 0.360800 ;
    PORT
      LAYER Metal3 ;
        RECT 667.800 21.280 668.360 21.840 ;
    END
  END bidir_pu[16]
  PIN bidir_pu[17]
    DIRECTION OUTPUT ;
    USE SIGNAL ;
    ANTENNADIFFAREA 0.360800 ;
    PORT
      LAYER Metal2 ;
        RECT 262.080 685.720 262.640 686.280 ;
    END
  END bidir_pu[17]
  PIN bidir_pu[18]
    DIRECTION OUTPUT ;
    USE SIGNAL ;
    ANTENNADIFFAREA 0.360800 ;
    PORT
      LAYER Metal3 ;
        RECT 667.800 684.320 668.360 684.880 ;
    END
  END bidir_pu[18]
  PIN bidir_pu[19]
    DIRECTION OUTPUT ;
    USE SIGNAL ;
    ANTENNADIFFAREA 0.360800 ;
    PORT
      LAYER Metal3 ;
        RECT 667.800 115.360 668.360 115.920 ;
    END
  END bidir_pu[19]
  PIN bidir_pu[1]
    DIRECTION OUTPUT ;
    USE SIGNAL ;
    ANTENNADIFFAREA 0.360800 ;
    PORT
      LAYER Metal3 ;
        RECT 0.000 649.600 0.560 650.160 ;
    END
  END bidir_pu[1]
  PIN bidir_pu[2]
    DIRECTION OUTPUT ;
    USE SIGNAL ;
    ANTENNADIFFAREA 0.360800 ;
    PORT
      LAYER Metal3 ;
        RECT 667.800 45.920 668.360 46.480 ;
    END
  END bidir_pu[2]
  PIN bidir_pu[3]
    DIRECTION OUTPUT ;
    USE SIGNAL ;
    ANTENNADIFFAREA 0.360800 ;
    PORT
      LAYER Metal2 ;
        RECT 264.320 0.000 264.880 0.560 ;
    END
  END bidir_pu[3]
  PIN bidir_pu[4]
    DIRECTION OUTPUT ;
    USE SIGNAL ;
    ANTENNADIFFAREA 0.360800 ;
    PORT
      LAYER Metal3 ;
        RECT 667.800 641.760 668.360 642.320 ;
    END
  END bidir_pu[4]
  PIN bidir_pu[5]
    DIRECTION OUTPUT ;
    USE SIGNAL ;
    ANTENNADIFFAREA 0.360800 ;
    PORT
      LAYER Metal3 ;
        RECT 667.800 415.520 668.360 416.080 ;
    END
  END bidir_pu[5]
  PIN bidir_pu[6]
    DIRECTION OUTPUT ;
    USE SIGNAL ;
    ANTENNADIFFAREA 0.360800 ;
    PORT
      LAYER Metal2 ;
        RECT 639.520 0.000 640.080 0.560 ;
    END
  END bidir_pu[6]
  PIN bidir_pu[7]
    DIRECTION OUTPUT ;
    USE SIGNAL ;
    ANTENNADIFFAREA 0.360800 ;
    PORT
      LAYER Metal2 ;
        RECT 90.720 685.720 91.280 686.280 ;
    END
  END bidir_pu[7]
  PIN bidir_pu[8]
    DIRECTION OUTPUT ;
    USE SIGNAL ;
    ANTENNADIFFAREA 0.360800 ;
    PORT
      LAYER Metal3 ;
        RECT 667.800 464.800 668.360 465.360 ;
    END
  END bidir_pu[8]
  PIN bidir_pu[9]
    DIRECTION OUTPUT ;
    USE SIGNAL ;
    ANTENNADIFFAREA 0.360800 ;
    PORT
      LAYER Metal2 ;
        RECT 306.880 0.000 307.440 0.560 ;
    END
  END bidir_pu[9]
  PIN bidir_sl[0]
    DIRECTION OUTPUT ;
    USE SIGNAL ;
    ANTENNADIFFAREA 0.360800 ;
    PORT
      LAYER Metal2 ;
        RECT 323.680 685.720 324.240 686.280 ;
    END
  END bidir_sl[0]
  PIN bidir_sl[10]
    DIRECTION OUTPUT ;
    USE SIGNAL ;
    ANTENNADIFFAREA 0.360800 ;
    PORT
      LAYER Metal3 ;
        RECT 667.800 73.920 668.360 74.480 ;
    END
  END bidir_sl[10]
  PIN bidir_sl[11]
    DIRECTION OUTPUT ;
    USE SIGNAL ;
    ANTENNADIFFAREA 0.360800 ;
    PORT
      LAYER Metal2 ;
        RECT 607.040 0.000 607.600 0.560 ;
    END
  END bidir_sl[11]
  PIN bidir_sl[12]
    DIRECTION OUTPUT ;
    USE SIGNAL ;
    ANTENNADIFFAREA 0.360800 ;
    PORT
      LAYER Metal3 ;
        RECT 667.800 372.960 668.360 373.520 ;
    END
  END bidir_sl[12]
  PIN bidir_sl[13]
    DIRECTION OUTPUT ;
    USE SIGNAL ;
    ANTENNADIFFAREA 0.360800 ;
    PORT
      LAYER Metal2 ;
        RECT 336.000 685.720 336.560 686.280 ;
    END
  END bidir_sl[13]
  PIN bidir_sl[14]
    DIRECTION OUTPUT ;
    USE SIGNAL ;
    ANTENNADIFFAREA 0.360800 ;
    PORT
      LAYER Metal2 ;
        RECT 496.160 685.720 496.720 686.280 ;
    END
  END bidir_sl[14]
  PIN bidir_sl[15]
    DIRECTION OUTPUT ;
    USE SIGNAL ;
    ANTENNADIFFAREA 0.360800 ;
    PORT
      LAYER Metal3 ;
        RECT 667.800 411.040 668.360 411.600 ;
    END
  END bidir_sl[15]
  PIN bidir_sl[16]
    DIRECTION OUTPUT ;
    USE SIGNAL ;
    ANTENNADIFFAREA 0.360800 ;
    PORT
      LAYER Metal2 ;
        RECT 135.520 685.720 136.080 686.280 ;
    END
  END bidir_sl[16]
  PIN bidir_sl[17]
    DIRECTION OUTPUT ;
    USE SIGNAL ;
    ANTENNADIFFAREA 0.360800 ;
    PORT
      LAYER Metal2 ;
        RECT 381.920 0.000 382.480 0.560 ;
    END
  END bidir_sl[17]
  PIN bidir_sl[18]
    DIRECTION OUTPUT ;
    USE SIGNAL ;
    ANTENNADIFFAREA 0.360800 ;
    PORT
      LAYER Metal3 ;
        RECT 667.800 589.120 668.360 589.680 ;
    END
  END bidir_sl[18]
  PIN bidir_sl[19]
    DIRECTION OUTPUT ;
    USE SIGNAL ;
    ANTENNADIFFAREA 0.360800 ;
    PORT
      LAYER Metal2 ;
        RECT 210.560 685.720 211.120 686.280 ;
    END
  END bidir_sl[19]
  PIN bidir_sl[1]
    DIRECTION OUTPUT ;
    USE SIGNAL ;
    ANTENNADIFFAREA 0.360800 ;
    PORT
      LAYER Metal3 ;
        RECT 667.800 663.040 668.360 663.600 ;
    END
  END bidir_sl[1]
  PIN bidir_sl[2]
    DIRECTION OUTPUT ;
    USE SIGNAL ;
    ANTENNADIFFAREA 0.360800 ;
    PORT
      LAYER Metal2 ;
        RECT 248.640 0.000 249.200 0.560 ;
    END
  END bidir_sl[2]
  PIN bidir_sl[3]
    DIRECTION OUTPUT ;
    USE SIGNAL ;
    ANTENNADIFFAREA 0.536800 ;
    PORT
      LAYER Metal2 ;
        RECT 312.480 685.720 313.040 686.280 ;
    END
  END bidir_sl[3]
  PIN bidir_sl[4]
    DIRECTION OUTPUT ;
    USE SIGNAL ;
    ANTENNADIFFAREA 0.360800 ;
    PORT
      LAYER Metal3 ;
        RECT 667.800 660.800 668.360 661.360 ;
    END
  END bidir_sl[4]
  PIN bidir_sl[5]
    DIRECTION OUTPUT ;
    USE SIGNAL ;
    ANTENNADIFFAREA 0.360800 ;
    PORT
      LAYER Metal2 ;
        RECT 561.120 685.720 561.680 686.280 ;
    END
  END bidir_sl[5]
  PIN bidir_sl[6]
    DIRECTION OUTPUT ;
    USE SIGNAL ;
    ANTENNADIFFAREA 0.360800 ;
    PORT
      LAYER Metal3 ;
        RECT 0.000 361.760 0.560 362.320 ;
    END
  END bidir_sl[6]
  PIN bidir_sl[7]
    DIRECTION OUTPUT ;
    USE SIGNAL ;
    ANTENNADIFFAREA 0.360800 ;
    PORT
      LAYER Metal2 ;
        RECT 100.800 685.720 101.360 686.280 ;
    END
  END bidir_sl[7]
  PIN bidir_sl[8]
    DIRECTION OUTPUT ;
    USE SIGNAL ;
    ANTENNADIFFAREA 0.360800 ;
    PORT
      LAYER Metal2 ;
        RECT 421.120 685.720 421.680 686.280 ;
    END
  END bidir_sl[8]
  PIN bidir_sl[9]
    DIRECTION OUTPUT ;
    USE SIGNAL ;
    ANTENNADIFFAREA 0.360800 ;
    PORT
      LAYER Metal2 ;
        RECT 584.640 0.000 585.200 0.560 ;
    END
  END bidir_sl[9]
  PIN clk
    DIRECTION INPUT ;
    USE SIGNAL ;
    ANTENNAGATEAREA 4.738000 ;
    PORT
      LAYER Metal3 ;
        RECT 0.000 621.600 0.560 622.160 ;
    END
  END clk
  PIN input_in
    DIRECTION INPUT ;
    USE SIGNAL ;
    ANTENNAGATEAREA 0.396000 ;
    PORT
      LAYER Metal3 ;
        RECT 0.000 91.840 0.560 92.400 ;
    END
  END input_in
  PIN input_pd
    DIRECTION OUTPUT ;
    USE SIGNAL ;
    ANTENNADIFFAREA 0.360800 ;
    PORT
      LAYER Metal2 ;
        RECT 536.480 685.720 537.040 686.280 ;
    END
  END input_pd
  PIN input_pu
    DIRECTION OUTPUT ;
    USE SIGNAL ;
    ANTENNADIFFAREA 0.360800 ;
    PORT
      LAYER Metal3 ;
        RECT 667.800 661.920 668.360 662.480 ;
    END
  END input_pu
  PIN rst_n
    DIRECTION INPUT ;
    USE SIGNAL ;
    ANTENNAGATEAREA 0.396000 ;
    PORT
      LAYER Metal3 ;
        RECT 0.000 620.480 0.560 621.040 ;
    END
  END rst_n
  OBS
      LAYER Nwell ;
        RECT 6.290 15.250 661.790 670.750 ;
      LAYER Metal1 ;
        RECT 6.720 15.380 661.360 670.620 ;
      LAYER Metal2 ;
        RECT 0.140 685.420 34.420 685.720 ;
        RECT 37.820 685.420 70.260 685.720 ;
        RECT 71.420 685.420 90.420 685.720 ;
        RECT 91.580 685.420 92.660 685.720 ;
        RECT 93.820 685.420 100.500 685.720 ;
        RECT 101.660 685.420 135.220 685.720 ;
        RECT 136.380 685.420 154.260 685.720 ;
        RECT 155.420 685.420 192.340 685.720 ;
        RECT 193.500 685.420 208.020 685.720 ;
        RECT 209.180 685.420 210.260 685.720 ;
        RECT 211.420 685.420 221.460 685.720 ;
        RECT 222.620 685.420 230.420 685.720 ;
        RECT 231.580 685.420 261.780 685.720 ;
        RECT 262.940 685.420 290.900 685.720 ;
        RECT 292.060 685.420 312.180 685.720 ;
        RECT 313.340 685.420 322.260 685.720 ;
        RECT 324.540 685.420 335.700 685.720 ;
        RECT 336.860 685.420 358.100 685.720 ;
        RECT 359.260 685.420 414.100 685.720 ;
        RECT 415.260 685.420 420.820 685.720 ;
        RECT 421.980 685.420 482.420 685.720 ;
        RECT 483.580 685.420 495.860 685.720 ;
        RECT 497.020 685.420 536.180 685.720 ;
        RECT 537.340 685.420 552.980 685.720 ;
        RECT 554.140 685.420 560.820 685.720 ;
        RECT 561.980 685.420 565.300 685.720 ;
        RECT 566.460 685.420 660.100 685.720 ;
        RECT 0.140 0.860 660.100 685.420 ;
        RECT 0.140 0.560 0.820 0.860 ;
        RECT 82.620 0.560 84.820 0.860 ;
        RECT 85.980 0.560 108.340 0.860 ;
        RECT 109.500 0.560 110.580 0.860 ;
        RECT 111.740 0.560 127.380 0.860 ;
        RECT 129.660 0.560 135.220 0.860 ;
        RECT 136.380 0.560 149.780 0.860 ;
        RECT 150.940 0.560 160.980 0.860 ;
        RECT 162.140 0.560 172.180 0.860 ;
        RECT 174.460 0.560 186.740 0.860 ;
        RECT 187.900 0.560 196.820 0.860 ;
        RECT 197.980 0.560 204.660 0.860 ;
        RECT 206.940 0.560 212.500 0.860 ;
        RECT 214.780 0.560 248.340 0.860 ;
        RECT 249.500 0.560 264.020 0.860 ;
        RECT 265.180 0.560 275.220 0.860 ;
        RECT 276.380 0.560 306.580 0.860 ;
        RECT 307.740 0.560 340.180 0.860 ;
        RECT 341.340 0.560 342.420 0.860 ;
        RECT 344.700 0.560 360.340 0.860 ;
        RECT 361.500 0.560 381.620 0.860 ;
        RECT 382.780 0.560 418.580 0.860 ;
        RECT 419.740 0.560 449.940 0.860 ;
        RECT 451.100 0.560 495.860 0.860 ;
        RECT 497.020 0.560 498.100 0.860 ;
        RECT 500.380 0.560 532.820 0.860 ;
        RECT 533.980 0.560 584.340 0.860 ;
        RECT 585.500 0.560 598.900 0.860 ;
        RECT 600.060 0.560 606.740 0.860 ;
        RECT 607.900 0.560 622.420 0.860 ;
        RECT 623.580 0.560 639.220 0.860 ;
        RECT 640.380 0.560 660.100 0.860 ;
      LAYER Metal3 ;
        RECT 0.560 672.820 667.500 684.740 ;
        RECT 0.560 663.900 667.800 672.820 ;
        RECT 0.560 660.500 667.500 663.900 ;
        RECT 0.560 650.460 667.800 660.500 ;
        RECT 0.860 642.620 667.800 650.460 ;
        RECT 0.860 642.580 667.500 642.620 ;
        RECT 0.560 641.460 667.500 642.580 ;
        RECT 0.560 622.460 667.800 641.460 ;
        RECT 0.860 620.180 667.800 622.460 ;
        RECT 0.560 615.740 667.800 620.180 ;
        RECT 0.560 614.580 667.500 615.740 ;
        RECT 0.560 610.140 667.800 614.580 ;
        RECT 0.560 608.980 667.500 610.140 ;
        RECT 0.560 589.980 667.800 608.980 ;
        RECT 0.560 588.820 667.500 589.980 ;
        RECT 0.560 586.620 667.800 588.820 ;
        RECT 0.860 585.460 667.800 586.620 ;
        RECT 0.560 584.380 667.800 585.460 ;
        RECT 0.560 583.220 667.500 584.380 ;
        RECT 0.560 520.540 667.800 583.220 ;
        RECT 0.860 519.380 667.800 520.540 ;
        RECT 0.560 513.820 667.800 519.380 ;
        RECT 0.560 512.660 667.500 513.820 ;
        RECT 0.560 489.180 667.800 512.660 ;
        RECT 0.860 488.020 667.800 489.180 ;
        RECT 0.560 484.700 667.800 488.020 ;
        RECT 0.560 483.540 667.500 484.700 ;
        RECT 0.560 465.660 667.800 483.540 ;
        RECT 0.560 464.500 667.500 465.660 ;
        RECT 0.560 453.340 667.800 464.500 ;
        RECT 0.860 451.060 667.800 453.340 ;
        RECT 0.560 443.260 667.800 451.060 ;
        RECT 0.560 442.100 667.500 443.260 ;
        RECT 0.560 441.020 667.800 442.100 ;
        RECT 0.560 439.860 667.500 441.020 ;
        RECT 0.560 426.460 667.800 439.860 ;
        RECT 0.860 425.300 667.800 426.460 ;
        RECT 0.560 416.380 667.800 425.300 ;
        RECT 0.560 415.220 667.500 416.380 ;
        RECT 0.560 411.900 667.800 415.220 ;
        RECT 0.860 410.740 667.500 411.900 ;
        RECT 0.560 409.620 667.500 410.740 ;
        RECT 0.560 404.060 667.800 409.620 ;
        RECT 0.860 402.900 667.800 404.060 ;
        RECT 0.560 395.100 667.800 402.900 ;
        RECT 0.860 393.940 667.800 395.100 ;
        RECT 0.560 377.180 667.800 393.940 ;
        RECT 0.560 376.020 667.500 377.180 ;
        RECT 0.560 373.820 667.800 376.020 ;
        RECT 0.560 372.660 667.500 373.820 ;
        RECT 0.560 369.340 667.800 372.660 ;
        RECT 0.560 368.180 667.500 369.340 ;
        RECT 0.560 364.860 667.800 368.180 ;
        RECT 0.860 363.700 667.800 364.860 ;
        RECT 0.560 362.620 667.800 363.700 ;
        RECT 0.860 361.460 667.800 362.620 ;
        RECT 0.560 332.380 667.800 361.460 ;
        RECT 0.860 331.220 667.800 332.380 ;
        RECT 0.560 320.060 667.800 331.220 ;
        RECT 0.560 318.900 667.500 320.060 ;
        RECT 0.560 311.100 667.800 318.900 ;
        RECT 0.860 309.940 667.800 311.100 ;
        RECT 0.560 304.380 667.800 309.940 ;
        RECT 0.860 303.220 667.800 304.380 ;
        RECT 0.560 288.700 667.800 303.220 ;
        RECT 0.560 287.540 667.500 288.700 ;
        RECT 0.560 273.020 667.800 287.540 ;
        RECT 0.560 271.860 667.500 273.020 ;
        RECT 0.560 215.900 667.800 271.860 ;
        RECT 0.560 214.740 667.500 215.900 ;
        RECT 0.560 190.140 667.800 214.740 ;
        RECT 0.560 188.980 667.500 190.140 ;
        RECT 0.560 187.900 667.800 188.980 ;
        RECT 0.560 186.740 667.500 187.900 ;
        RECT 0.560 185.660 667.800 186.740 ;
        RECT 0.560 184.500 667.500 185.660 ;
        RECT 0.560 129.660 667.800 184.500 ;
        RECT 0.560 128.500 667.500 129.660 ;
        RECT 0.560 116.220 667.800 128.500 ;
        RECT 0.560 115.060 667.500 116.220 ;
        RECT 0.560 108.380 667.800 115.060 ;
        RECT 0.560 106.100 667.500 108.380 ;
        RECT 0.560 100.540 667.800 106.100 ;
        RECT 0.860 99.380 667.800 100.540 ;
        RECT 0.560 94.940 667.800 99.380 ;
        RECT 0.860 93.780 667.500 94.940 ;
        RECT 0.560 92.700 667.800 93.780 ;
        RECT 0.860 91.540 667.800 92.700 ;
        RECT 0.560 90.460 667.800 91.540 ;
        RECT 0.860 89.300 667.800 90.460 ;
        RECT 0.560 83.740 667.800 89.300 ;
        RECT 0.560 82.580 667.500 83.740 ;
        RECT 0.560 74.780 667.800 82.580 ;
        RECT 0.860 73.620 667.500 74.780 ;
        RECT 0.560 72.540 667.800 73.620 ;
        RECT 0.860 71.380 667.800 72.540 ;
        RECT 0.560 69.180 667.800 71.380 ;
        RECT 0.860 68.020 667.800 69.180 ;
        RECT 0.560 46.780 667.800 68.020 ;
        RECT 0.560 45.620 667.500 46.780 ;
        RECT 0.560 36.700 667.800 45.620 ;
        RECT 0.560 35.540 667.500 36.700 ;
        RECT 0.560 33.340 667.800 35.540 ;
        RECT 0.560 31.060 667.500 33.340 ;
        RECT 0.560 25.500 667.800 31.060 ;
        RECT 0.560 20.980 667.500 25.500 ;
        RECT 0.560 13.180 667.800 20.980 ;
        RECT 0.860 7.540 667.800 13.180 ;
        RECT 0.560 0.700 667.800 7.540 ;
      LAYER Metal4 ;
        RECT 32.620 25.290 175.540 563.830 ;
        RECT 177.740 25.290 178.840 563.830 ;
        RECT 181.040 25.290 329.140 563.830 ;
        RECT 331.340 25.290 332.440 563.830 ;
        RECT 334.640 25.290 482.740 563.830 ;
        RECT 484.940 25.290 486.040 563.830 ;
        RECT 488.240 25.290 545.300 563.830 ;
      LAYER Metal5 ;
        RECT 32.540 496.570 538.100 546.970 ;
        RECT 32.540 493.270 538.100 493.770 ;
        RECT 32.540 343.390 538.100 490.470 ;
        RECT 32.540 340.090 538.100 340.590 ;
        RECT 32.540 230.630 538.100 337.290 ;
  END
END chip_core
END LIBRARY

